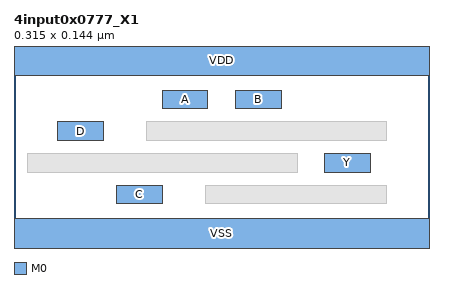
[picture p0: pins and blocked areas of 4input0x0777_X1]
MACRO 4input0x0777_X1
  CLASS CORE ;
  ORIGIN 0 0 ;
  FOREIGN 4input0x0777_X1 0 0 ;
  SIZE 0.3150 BY 0.1440 ;
  SYMMETRY X Y ;
  SITE coresite ;
  PIN A
    DIRECTION INPUT ;
    USE SIGNAL ;
    PORT
      LAYER M0 ;
        RECT 0.1125 0.1010 0.1470 0.1150 ;
    END
  END A
  PIN B
    DIRECTION INPUT ;
    USE SIGNAL ;
    PORT
      LAYER M0 ;
        RECT 0.1680 0.1010 0.2025 0.1150 ;
    END
  END B
  PIN C
    DIRECTION INPUT ;
    USE SIGNAL ;
    PORT
      LAYER M0 ;
        RECT 0.0780 0.0290 0.1125 0.0430 ;
    END
  END C
  PIN D
    DIRECTION INPUT ;
    USE SIGNAL ;
    PORT
      LAYER M0 ;
        RECT 0.0330 0.0770 0.0675 0.0910 ;
    END
  END D
  PIN Y
    DIRECTION OUTPUT ;
    USE SIGNAL ;
    PORT
      LAYER M0 ;
        RECT 0.2355 0.0530 0.2700 0.0670 ;
    END
  END Y
  PIN VDD
    DIRECTION INOUT ;
    USE POWER ;
    SHAPE ABUTMENT ;
    PORT
      LAYER M0 ;
        RECT 0.0000 0.1260 0.3150 0.1620 ;
    END
  END VDD
  PIN VSS
    DIRECTION INOUT ;
    USE GROUND ;
    SHAPE ABUTMENT ;
    PORT
      LAYER M0 ;
        RECT 0.0000 -0.0180 0.3150 0.0180 ;
    END
  END VSS
  OBS
    LAYER M0 ;
      RECT 0.1455 0.0290 0.2820 0.0430 ;
      RECT 0.0105 0.0530 0.2145 0.0670 ;
      RECT 0.1005 0.0770 0.2820 0.0910 ;
  END
END 4input0x0777_X1
